VERSION 5.8 ;
NAMESCASESENSITIVE ON ;
BUSBITCHARS "[]" ;
DIVIDERCHAR "/" ;

PROPERTYDEFINITIONS
END PROPERTYDEFINITIONS

UNITS
    DATABASE MICRONS 2000 ;
END UNITS

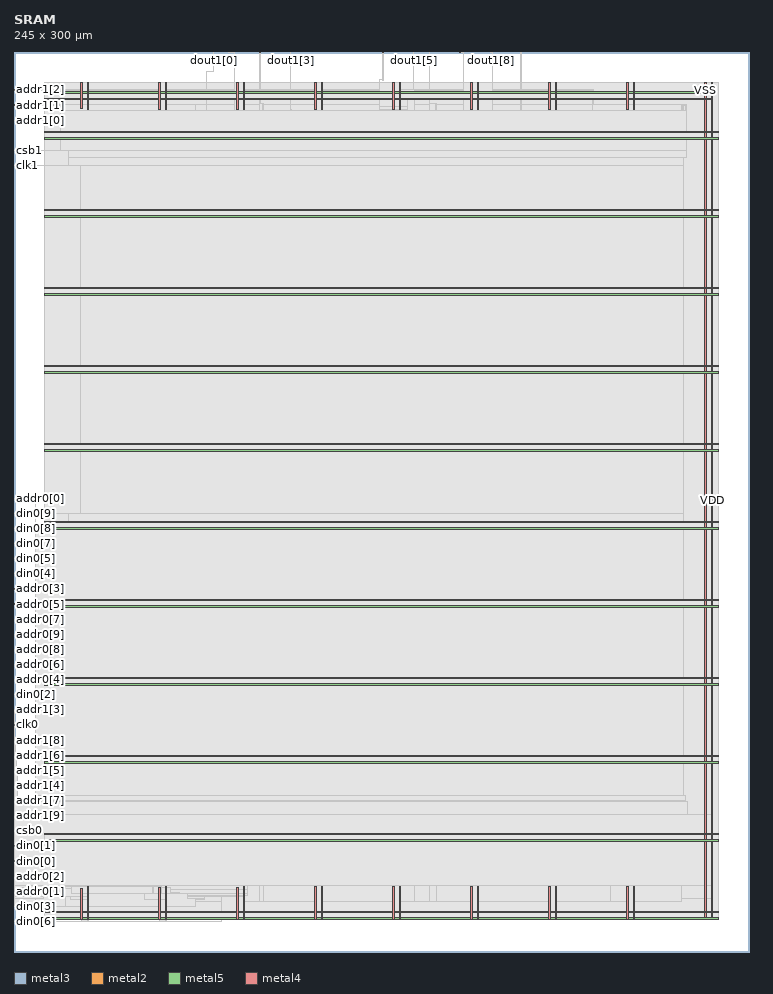
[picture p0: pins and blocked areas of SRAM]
MACRO SRAM
    CLASS BLOCK ;
    SIZE 245 BY 300 ;
    PIN addr0[0]
        DIRECTION INPUT ; 
        USE SIGNAL ; 
        PORT
            LAYER metal3 ;
              RECT  0 151.235 0.07 151.305 ;
        END
    END addr0[0]
    PIN addr0[1]
        DIRECTION INPUT ; 
        USE SIGNAL ; 
        PORT
            LAYER metal3 ;
              RECT  0 20.195 0.07 20.265 ;
        END
    END addr0[1]
    PIN addr0[2]
        DIRECTION INPUT ; 
        USE SIGNAL ; 
        PORT
            LAYER metal3 ;
              RECT  0 25.235 0.07 25.305 ;
        END
    END addr0[2]
    PIN addr0[3]
        DIRECTION INPUT ; 
        USE SIGNAL ; 
        PORT
            LAYER metal3 ;
              RECT  0 120.995 0.07 121.065 ;
        END
    END addr0[3]
    PIN addr0[4]
        DIRECTION INPUT ; 
        USE SIGNAL ; 
        PORT
            LAYER metal3 ;
              RECT  0 90.755 0.07 90.825 ;
        END
    END addr0[4]
    PIN addr0[5]
        DIRECTION INPUT ; 
        USE SIGNAL ; 
        PORT
            LAYER metal3 ;
              RECT  0 115.955 0.07 116.025 ;
        END
    END addr0[5]
    PIN addr0[6]
        DIRECTION INPUT ; 
        USE SIGNAL ; 
        PORT
            LAYER metal3 ;
              RECT  0 95.795 0.07 95.865 ;
        END
    END addr0[6]
    PIN addr0[7]
        DIRECTION INPUT ; 
        USE SIGNAL ; 
        PORT
            LAYER metal3 ;
              RECT  0 110.915 0.07 110.985 ;
        END
    END addr0[7]
    PIN addr0[8]
        DIRECTION INPUT ; 
        USE SIGNAL ; 
        PORT
            LAYER metal3 ;
              RECT  0 100.835 0.07 100.905 ;
        END
    END addr0[8]
    PIN addr0[9]
        DIRECTION INPUT ; 
        USE SIGNAL ; 
        PORT
            LAYER metal3 ;
              RECT  0 105.875 0.07 105.945 ;
        END
    END addr0[9]
    PIN addr1[0]
        DIRECTION INPUT ; 
        USE SIGNAL ; 
        PORT
            LAYER metal3 ;
              RECT  0 277.235 0.07 277.305 ;
        END
    END addr1[0]
    PIN addr1[1]
        DIRECTION INPUT ; 
        USE SIGNAL ; 
        PORT
            LAYER metal3 ;
              RECT  0 282.275 0.07 282.345 ;
        END
    END addr1[1]
    PIN addr1[2]
        DIRECTION INPUT ; 
        USE SIGNAL ; 
        PORT
            LAYER metal3 ;
              RECT  0 287.315 0.07 287.385 ;
        END
    END addr1[2]
    PIN addr1[3]
        DIRECTION INPUT ; 
        USE SIGNAL ; 
        PORT
            LAYER metal3 ;
              RECT  0 80.675 0.07 80.745 ;
        END
    END addr1[3]
    PIN addr1[4]
        DIRECTION INPUT ; 
        USE SIGNAL ; 
        PORT
            LAYER metal3 ;
              RECT  0 55.475 0.07 55.545 ;
        END
    END addr1[4]
    PIN addr1[5]
        DIRECTION INPUT ; 
        USE SIGNAL ; 
        PORT
            LAYER metal3 ;
              RECT  0 60.515 0.07 60.585 ;
        END
    END addr1[5]
    PIN addr1[6]
        DIRECTION INPUT ; 
        USE SIGNAL ; 
        PORT
            LAYER metal3 ;
              RECT  0 65.555 0.07 65.625 ;
        END
    END addr1[6]
    PIN addr1[7]
        DIRECTION INPUT ; 
        USE SIGNAL ; 
        PORT
            LAYER metal3 ;
              RECT  0 50.435 0.07 50.505 ;
        END
    END addr1[7]
    PIN addr1[8]
        DIRECTION INPUT ; 
        USE SIGNAL ; 
        PORT
            LAYER metal3 ;
              RECT  0 70.595 0.07 70.665 ;
        END
    END addr1[8]
    PIN addr1[9]
        DIRECTION INPUT ; 
        USE SIGNAL ; 
        PORT
            LAYER metal3 ;
              RECT  0 45.395 0.07 45.465 ;
        END
    END addr1[9]
    PIN clk0
        DIRECTION INPUT ; 
        USE CLOCK ; 
        PORT
            LAYER metal3 ;
              RECT  0 75.635 0.07 75.705 ;
        END
    END clk0
    PIN clk1
        DIRECTION INPUT ; 
        USE CLOCK ; 
        PORT
            LAYER metal3 ;
              RECT  0 262.115 0.07 262.185 ;
        END
    END clk1
    PIN csb0
        DIRECTION INPUT ; 
        USE SIGNAL ; 
        PORT
            LAYER metal3 ;
              RECT  0 40.355 0.07 40.425 ;
        END
    END csb0
    PIN csb1
        DIRECTION INPUT ; 
        USE SIGNAL ; 
        PORT
            LAYER metal3 ;
              RECT  0 267.155 0.07 267.225 ;
        END
    END csb1
    PIN din0[0]
        DIRECTION INPUT ; 
        USE SIGNAL ; 
        PORT
            LAYER metal3 ;
              RECT  0 30.275 0.07 30.345 ;
        END
    END din0[0]
    PIN din0[1]
        DIRECTION INPUT ; 
        USE SIGNAL ; 
        PORT
            LAYER metal3 ;
              RECT  0 35.315 0.07 35.385 ;
        END
    END din0[1]
    PIN din0[2]
        DIRECTION INPUT ; 
        USE SIGNAL ; 
        PORT
            LAYER metal3 ;
              RECT  0 85.715 0.07 85.785 ;
        END
    END din0[2]
    PIN din0[3]
        DIRECTION INPUT ; 
        USE SIGNAL ; 
        PORT
            LAYER metal3 ;
              RECT  0 15.155 0.07 15.225 ;
        END
    END din0[3]
    PIN din0[4]
        DIRECTION INPUT ; 
        USE SIGNAL ; 
        PORT
            LAYER metal3 ;
              RECT  0 126.035 0.07 126.105 ;
        END
    END din0[4]
    PIN din0[5]
        DIRECTION INPUT ; 
        USE SIGNAL ; 
        PORT
            LAYER metal3 ;
              RECT  0 131.075 0.07 131.145 ;
        END
    END din0[5]
    PIN din0[6]
        DIRECTION INPUT ; 
        USE SIGNAL ; 
        PORT
            LAYER metal3 ;
              RECT  0 10.115 0.07 10.185 ;
        END
    END din0[6]
    PIN din0[7]
        DIRECTION INPUT ; 
        USE SIGNAL ; 
        PORT
            LAYER metal3 ;
              RECT  0 136.115 0.07 136.185 ;
        END
    END din0[7]
    PIN din0[8]
        DIRECTION INPUT ; 
        USE SIGNAL ; 
        PORT
            LAYER metal3 ;
              RECT  0 141.155 0.07 141.225 ;
        END
    END din0[8]
    PIN din0[9]
        DIRECTION INPUT ; 
        USE SIGNAL ; 
        PORT
            LAYER metal3 ;
              RECT  0 146.195 0.07 146.265 ;
        END
    END din0[9]
    PIN dout1[0]
        DIRECTION OUTPUT ; 
        USE SIGNAL ; 
        PORT
            LAYER metal2 ;
              RECT  66.56 299.93 66.63 300 ;
        END
    END dout1[0]
    PIN dout1[1]
        DIRECTION OUTPUT ; 
        USE SIGNAL ; 
        PORT
            LAYER metal2 ;
              RECT  71.69 299.93 71.76 300 ;
        END
    END dout1[1]
    PIN dout1[2]
        DIRECTION OUTPUT ; 
        USE SIGNAL ; 
        PORT
            LAYER metal2 ;
              RECT  81.95 299.93 82.02 300 ;
        END
    END dout1[2]
    PIN dout1[3]
        DIRECTION OUTPUT ; 
        USE SIGNAL ; 
        PORT
            LAYER metal2 ;
              RECT  92.21 299.93 92.28 300 ;
        END
    END dout1[3]
    PIN dout1[4]
        DIRECTION OUTPUT ; 
        USE SIGNAL ; 
        PORT
            LAYER metal2 ;
              RECT  122.99 299.93 123.06 300 ;
        END
    END dout1[4]
    PIN dout1[5]
        DIRECTION OUTPUT ; 
        USE SIGNAL ; 
        PORT
            LAYER metal2 ;
              RECT  133.25 299.93 133.32 300 ;
        END
    END dout1[5]
    PIN dout1[6]
        DIRECTION OUTPUT ; 
        USE SIGNAL ; 
        PORT
            LAYER metal2 ;
              RECT  138.38 299.93 138.45 300 ;
        END
    END dout1[6]
    PIN dout1[7]
        DIRECTION OUTPUT ; 
        USE SIGNAL ; 
        PORT
            LAYER metal2 ;
              RECT  148.64 299.93 148.71 300 ;
        END
    END dout1[7]
    PIN dout1[8]
        DIRECTION OUTPUT ; 
        USE SIGNAL ; 
        PORT
            LAYER metal2 ;
              RECT  158.9 299.93 158.97 300 ;
        END
    END dout1[8]
    PIN dout1[9]
        DIRECTION OUTPUT ; 
        USE SIGNAL ; 
        PORT
            LAYER metal2 ;
              RECT  169.16 299.93 169.23 300 ;
        END
    END dout1[9]
    PIN VSS
        DIRECTION INOUT ; 
        USE GROUND ; 
        PORT
            LAYER metal5 ;
              RECT  10.07 286.26 232.92 286.76 ;
              RECT  10.07 270.95 234.84 271.45 ;
              RECT  10.07 244.95 234.84 245.45 ;
              RECT  10.07 218.95 234.84 219.45 ;
              RECT  10.07 192.95 234.84 193.45 ;
              RECT  10.07 166.95 234.84 167.45 ;
              RECT  10.07 140.95 234.84 141.45 ;
              RECT  10.07 114.95 234.84 115.45 ;
              RECT  10.07 88.95 234.84 89.45 ;
              RECT  10.07 62.95 234.84 63.45 ;
              RECT  10.07 36.95 234.84 37.45 ;
              RECT  10.07 10.95 234.84 11.45 ;
            LAYER metal4 ;
              RECT  230.32 10.95 230.82 289.84 ;
              RECT  204.32 280.82 204.82 289.84 ;
              RECT  204.32 10.95 204.82 21.79 ;
              RECT  178.32 280.82 178.82 289.84 ;
              RECT  178.32 10.95 178.82 21.79 ;
              RECT  152.32 280.82 152.82 289.84 ;
              RECT  152.32 10.95 152.82 21.79 ;
              RECT  126.32 280.82 126.82 289.84 ;
              RECT  126.32 10.95 126.82 21.79 ;
              RECT  100.32 280.82 100.82 289.84 ;
              RECT  100.32 10.95 100.82 21.79 ;
              RECT  74.32 280.82 74.82 289.84 ;
              RECT  74.32 10.95 74.82 21.65 ;
              RECT  48.32 280.82 48.82 289.84 ;
              RECT  48.32 10.95 48.82 21.65 ;
              RECT  22.32 281.32 22.82 289.84 ;
              RECT  22.32 10.95 22.82 21.29 ;
        END
    END VSS
    PIN VDD
        DIRECTION INOUT ; 
        USE POWER ; 
        PORT
            LAYER metal5 ;
              RECT  10.07 284.02 232.92 284.52 ;
              RECT  10.07 273.05 234.84 273.55 ;
              RECT  10.07 247.05 234.84 247.55 ;
              RECT  10.07 221.05 234.84 221.55 ;
              RECT  10.07 195.05 234.84 195.55 ;
              RECT  10.07 169.05 234.84 169.55 ;
              RECT  10.07 143.05 234.84 143.55 ;
              RECT  10.07 117.05 234.84 117.55 ;
              RECT  10.07 91.05 234.84 91.55 ;
              RECT  10.07 65.05 234.84 65.55 ;
              RECT  10.07 39.05 234.84 39.55 ;
              RECT  10.07 13.05 234.84 13.55 ;
            LAYER metal4 ;
              RECT  232.42 11.16 232.92 289.87 ;
              RECT  206.42 280.82 206.92 289.87 ;
              RECT  206.42 11.16 206.92 21.79 ;
              RECT  180.42 280.82 180.92 289.87 ;
              RECT  180.42 11.16 180.92 21.79 ;
              RECT  154.42 280.82 154.92 289.87 ;
              RECT  154.42 11.16 154.92 21.79 ;
              RECT  128.42 280.82 128.92 289.87 ;
              RECT  128.42 11.16 128.92 21.79 ;
              RECT  102.42 280.82 102.92 289.87 ;
              RECT  102.42 11.16 102.92 21.79 ;
              RECT  76.42 280.82 76.92 289.87 ;
              RECT  76.42 11.16 76.92 21.79 ;
              RECT  50.42 280.82 50.92 289.87 ;
              RECT  50.42 11.16 50.92 21.79 ;
              RECT  24.42 280.82 24.92 289.87 ;
              RECT  24.42 11.16 24.92 21.79 ;
        END
    END VDD
    OBS
      LAYER metal1 ;
        RECT  10.07 11.115 234.84 289.885 ;
      LAYER metal2 ;
        RECT  22.34 11.13 22.8 12.53 ;
        RECT  48.34 11.13 48.8 12.53 ;
        RECT  74.34 11.13 74.8 12.53 ;
        RECT  100.34 11.13 100.8 12.53 ;
        RECT  126.34 11.13 126.8 12.53 ;
        RECT  152.34 11.13 152.8 12.53 ;
        RECT  178.34 11.13 178.8 12.53 ;
        RECT  204.34 11.13 204.8 12.53 ;
        RECT  230.34 11.13 230.8 12.53 ;
        RECT  223.31 18.34 223.38 19.88 ;
        RECT  22.34 12.53 24.9 22.2 ;
        RECT  48.34 12.53 50.9 22.2 ;
        RECT  74.34 12.53 76.9 22.2 ;
        RECT  100.34 12.53 102.9 22.2 ;
        RECT  126.34 12.53 128.9 22.2 ;
        RECT  152.34 12.53 154.9 22.2 ;
        RECT  178.34 12.53 180.9 22.2 ;
        RECT  204.34 12.53 206.9 22.2 ;
        RECT  223.12 19.88 223.38 22.2 ;
        RECT  22.295 22.2 223.38 43.05 ;
        RECT  22.295 43.05 223.19 55.02 ;
        RECT  22.295 55.02 222.96 280.41 ;
        RECT  22.34 280.41 24.9 288.47 ;
        RECT  48.34 280.41 50.9 288.47 ;
        RECT  74.34 280.41 76.9 288.47 ;
        RECT  100.34 280.41 102.9 288.47 ;
        RECT  126.34 280.41 128.9 288.47 ;
        RECT  152.34 280.41 154.9 288.47 ;
        RECT  178.34 280.41 180.9 288.47 ;
        RECT  204.34 280.41 206.9 288.47 ;
        RECT  230.34 12.53 232.9 288.47 ;
        RECT  24.44 288.47 24.9 289.87 ;
        RECT  50.44 288.47 50.9 289.87 ;
        RECT  76.44 288.47 76.9 289.87 ;
        RECT  102.44 288.47 102.9 289.87 ;
        RECT  128.44 288.47 128.9 289.87 ;
        RECT  154.44 288.47 154.9 289.87 ;
        RECT  180.44 288.47 180.9 289.87 ;
        RECT  206.44 288.47 206.9 289.87 ;
        RECT  232.44 288.47 232.9 289.87 ;
        RECT  66.56 293.44 66.63 299.965 ;
        RECT  71.69 299.74 71.76 299.965 ;
        RECT  81.95 280.41 82.02 299.965 ;
        RECT  92.21 299.74 92.28 299.965 ;
        RECT  122.99 290.64 123.06 299.965 ;
        RECT  133.25 284.9 133.32 299.965 ;
        RECT  138.38 280.41 138.45 299.965 ;
        RECT  148.64 299.74 148.71 299.965 ;
        RECT  158.9 299.74 158.97 299.965 ;
        RECT  169.16 299.74 169.23 299.965 ;
      LAYER metal3 ;
        RECT  0.025 16.975 0.035 17.045 ;
        RECT  0.025 80.675 0.165 80.745 ;
        RECT  0.035 15.155 0.305 17.045 ;
        RECT  0.035 20.195 0.305 20.265 ;
        RECT  0.035 70.595 0.445 70.665 ;
        RECT  0.035 65.555 0.725 65.625 ;
        RECT  0.035 60.515 1.005 60.585 ;
        RECT  0.035 55.475 1.285 55.545 ;
        RECT  0.035 50.435 1.565 50.505 ;
        RECT  0.035 45.395 1.845 45.465 ;
        RECT  0.035 30.275 2.125 30.345 ;
        RECT  0.035 151.235 7.165 151.305 ;
        RECT  0.035 85.715 9.965 85.785 ;
        RECT  0.035 35.315 11.505 35.385 ;
        RECT  0.035 25.235 11.645 25.305 ;
        RECT  0.035 40.355 11.645 40.425 ;
        RECT  0.035 141.155 12.765 141.225 ;
        RECT  0.035 282.275 15.425 282.345 ;
        RECT  0.035 131.075 15.565 131.145 ;
        RECT  0.035 267.155 15.565 267.225 ;
        RECT  0.035 120.995 15.845 121.065 ;
        RECT  15.425 282.275 17.105 282.485 ;
        RECT  0.305 15.155 17.245 20.265 ;
        RECT  0.035 277.235 17.245 277.305 ;
        RECT  17.105 282.275 18.225 282.625 ;
        RECT  0.035 146.195 18.365 146.265 ;
        RECT  0.035 262.115 18.365 262.185 ;
        RECT  0.035 136.115 18.645 136.185 ;
        RECT  0.035 126.035 18.925 126.105 ;
        RECT  0.035 90.755 19.065 90.825 ;
        RECT  11.505 35.315 19.205 37.205 ;
        RECT  0.035 115.955 19.205 116.025 ;
        RECT  0.035 95.795 19.905 95.865 ;
        RECT  0.035 100.835 20.185 100.905 ;
        RECT  19.205 37.135 21.305 37.205 ;
        RECT  19.065 90.755 21.62 92.785 ;
        RECT  19.905 95.795 21.62 97.685 ;
        RECT  17.245 15.155 22.155 19.845 ;
        RECT  21.305 37.135 22.155 38.325 ;
        RECT  15.705 87.675 22.155 87.745 ;
        RECT  21.62 90.755 22.155 97.685 ;
        RECT  20.185 100.835 22.155 102.585 ;
        RECT  18.225 282.135 22.155 282.625 ;
        RECT  22.155 15.155 22.295 22.76 ;
        RECT  22.155 37.1 22.295 38.325 ;
        RECT  0.035 75.635 22.295 75.705 ;
        RECT  22.155 87.67 22.295 102.63 ;
        RECT  0.035 105.875 22.295 105.945 ;
        RECT  0.035 110.915 22.295 110.985 ;
        RECT  22.155 279.85 22.295 282.625 ;
        RECT  0.035 10.115 22.34 10.185 ;
        RECT  22.295 15.155 22.34 282.625 ;
        RECT  0.035 287.315 22.34 287.385 ;
        RECT  22.34 10.115 24.44 288.47 ;
        RECT  24.44 10.115 24.9 289.87 ;
        RECT  24.9 10.115 48.34 10.185 ;
        RECT  24.9 15.155 48.34 282.625 ;
        RECT  24.9 287.315 48.34 287.385 ;
        RECT  48.34 10.115 50.44 288.47 ;
        RECT  50.44 10.115 50.9 289.87 ;
        RECT  50.9 15.155 60.645 282.625 ;
        RECT  64.145 293.475 66.665 293.545 ;
        RECT  50.9 10.115 69.325 10.185 ;
        RECT  71.655 299.775 73.525 299.845 ;
        RECT  60.645 16.975 74.34 282.625 ;
        RECT  50.9 287.315 74.34 287.385 ;
        RECT  74.34 11.13 74.8 288.47 ;
        RECT  74.8 12.53 76.44 288.47 ;
        RECT  76.44 12.53 76.9 289.87 ;
        RECT  76.9 16.975 81.915 282.625 ;
        RECT  81.915 16.975 83.045 282.765 ;
        RECT  92.145 299.775 92.315 299.845 ;
        RECT  83.045 16.975 100.34 282.625 ;
        RECT  76.9 287.315 100.34 287.385 ;
        RECT  100.34 11.13 100.8 288.47 ;
        RECT  100.8 12.53 102.44 288.47 ;
        RECT  102.44 12.53 102.9 289.87 ;
        RECT  121.825 290.675 123.095 290.745 ;
        RECT  102.9 16.975 126.34 282.625 ;
        RECT  102.9 287.315 126.34 287.385 ;
        RECT  126.34 11.13 126.8 288.47 ;
        RECT  126.8 12.53 128.44 288.47 ;
        RECT  128.44 12.53 128.9 289.87 ;
        RECT  128.9 16.975 133.355 287.385 ;
        RECT  133.355 16.975 138.345 282.625 ;
        RECT  138.345 16.975 140.725 282.765 ;
        RECT  148.605 299.775 149.965 299.845 ;
        RECT  140.725 16.975 152.34 282.625 ;
        RECT  133.355 287.315 152.34 287.385 ;
        RECT  152.34 11.13 152.8 288.47 ;
        RECT  152.8 12.53 154.44 288.47 ;
        RECT  154.44 12.53 154.9 289.87 ;
        RECT  158.865 299.775 159.485 299.845 ;
        RECT  168.865 299.775 169.265 299.845 ;
        RECT  154.9 16.975 178.34 282.625 ;
        RECT  154.9 287.315 178.34 287.385 ;
        RECT  178.34 11.13 178.8 288.47 ;
        RECT  178.8 12.53 180.44 288.47 ;
        RECT  180.44 12.53 180.9 289.87 ;
        RECT  180.9 287.315 193.085 287.385 ;
        RECT  180.9 16.975 198.965 282.625 ;
        RECT  198.965 16.975 204.34 282.485 ;
        RECT  204.34 11.13 204.8 288.47 ;
        RECT  204.8 12.53 206.44 288.47 ;
        RECT  206.44 12.53 206.9 289.87 ;
        RECT  206.9 16.975 222.485 282.485 ;
        RECT  222.485 17.815 222.96 282.485 ;
        RECT  222.96 17.815 223.1 22.76 ;
        RECT  222.96 40.74 223.1 55.7 ;
        RECT  222.96 264.705 223.1 265.08 ;
        RECT  222.96 279.85 223.1 282.485 ;
        RECT  223.1 17.815 223.225 19.985 ;
        RECT  223.1 54.915 223.225 54.985 ;
        RECT  223.1 40.775 223.415 52.045 ;
        RECT  223.1 264.775 223.57 265.01 ;
        RECT  223.415 45.675 223.885 52.045 ;
        RECT  223.57 264.775 223.885 264.985 ;
        RECT  223.1 282.135 223.885 282.485 ;
        RECT  223.225 17.815 224.165 19.845 ;
        RECT  223.885 45.675 224.165 50.085 ;
        RECT  223.885 264.915 224.165 264.985 ;
        RECT  223.885 282.415 224.165 282.485 ;
        RECT  224.165 17.815 224.445 19.285 ;
        RECT  224.165 50.015 224.445 50.085 ;
        RECT  224.445 17.815 224.725 19.145 ;
        RECT  224.165 45.675 224.725 45.745 ;
        RECT  224.725 17.815 225.005 17.885 ;
        RECT  223.415 40.775 225.005 40.845 ;
        RECT  230.34 11.13 230.8 288.47 ;
        RECT  230.8 12.53 232.44 288.47 ;
        RECT  232.44 12.53 232.9 289.87 ;
      LAYER metal4 ;
        RECT  69.185 10.08 69.325 10.95 ;
        RECT  22.32 10.95 22.82 11.16 ;
        RECT  48.32 10.95 48.82 11.16 ;
        RECT  69.185 10.95 74.82 11.16 ;
        RECT  100.32 10.95 100.82 11.16 ;
        RECT  126.32 10.95 126.82 11.16 ;
        RECT  152.32 10.95 152.82 11.16 ;
        RECT  178.32 10.95 178.82 11.16 ;
        RECT  204.32 10.95 204.82 11.16 ;
        RECT  230.32 10.95 230.82 11.16 ;
        RECT  48.32 11.16 50.92 17.5 ;
        RECT  22.32 11.16 24.92 17.64 ;
        RECT  60.505 15.12 60.645 17.64 ;
        RECT  0.025 16.94 0.165 17.78 ;
        RECT  7.025 17.5 7.165 17.78 ;
        RECT  222.345 16.94 222.485 17.78 ;
        RECT  230.32 11.16 232.92 17.78 ;
        RECT  0.025 17.78 7.165 17.92 ;
        RECT  60.505 17.64 63.445 17.92 ;
        RECT  0.025 17.92 9.965 18.48 ;
        RECT  18.785 17.64 24.92 18.48 ;
        RECT  57.705 17.92 63.445 18.48 ;
        RECT  69.185 11.16 76.92 18.48 ;
        RECT  57.705 18.48 76.92 18.76 ;
        RECT  43.425 17.5 50.92 19.6 ;
        RECT  57.705 18.76 77.725 19.6 ;
        RECT  43.425 19.6 77.725 20.72 ;
        RECT  0.025 18.48 24.92 22.2 ;
        RECT  43.425 20.72 77.885 22.2 ;
        RECT  100.32 11.16 102.92 22.2 ;
        RECT  126.32 11.16 128.92 22.2 ;
        RECT  152.32 11.16 154.92 22.2 ;
        RECT  178.32 11.16 180.92 22.2 ;
        RECT  204.32 11.16 206.92 22.2 ;
        RECT  222.345 17.78 232.92 22.2 ;
        RECT  0.025 22.2 232.92 45.78 ;
        RECT  0.025 45.78 224.445 50.12 ;
        RECT  0.025 50.12 223.885 50.54 ;
        RECT  7.025 50.54 223.885 52.08 ;
        RECT  0.025 50.54 1.285 55.58 ;
        RECT  0.025 55.58 1.005 60.62 ;
        RECT  0.025 60.62 0.725 65.66 ;
        RECT  0.025 65.66 0.445 70.7 ;
        RECT  0.025 70.7 0.165 80.78 ;
        RECT  7.025 52.08 223.1 141.26 ;
        RECT  18.225 141.26 223.1 146.3 ;
        RECT  7.025 141.26 7.165 151.34 ;
        RECT  22.155 146.3 223.1 262.08 ;
        RECT  18.225 262.08 223.1 264.74 ;
        RECT  18.225 264.74 223.885 264.88 ;
        RECT  18.225 264.88 224.165 267.12 ;
        RECT  15.425 267.12 224.165 280.41 ;
        RECT  222.4 280.41 224.165 280.55 ;
        RECT  82.885 280.41 83.045 280.98 ;
        RECT  92.145 280.41 92.425 280.98 ;
        RECT  121.745 280.41 131.285 280.98 ;
        RECT  140.545 280.41 140.725 280.98 ;
        RECT  168.745 280.41 169.005 280.98 ;
        RECT  64.085 280.41 64.285 281.82 ;
        RECT  121.825 280.98 131.285 281.82 ;
        RECT  223.745 280.55 224.165 282.24 ;
        RECT  192.945 280.41 206.92 282.38 ;
        RECT  15.425 280.41 24.92 282.52 ;
        RECT  224.025 282.24 224.165 282.52 ;
        RECT  17.105 282.52 24.92 282.66 ;
        RECT  198.825 282.38 206.92 282.66 ;
        RECT  82.905 280.98 83.045 282.8 ;
        RECT  140.585 280.98 140.725 282.8 ;
        RECT  121.825 281.82 131.205 285.04 ;
        RECT  192.945 282.38 193.085 287.42 ;
        RECT  22.32 282.66 24.92 289.84 ;
        RECT  48.32 280.41 50.92 289.84 ;
        RECT  100.32 280.41 102.92 289.84 ;
        RECT  121.825 285.04 128.92 289.84 ;
        RECT  178.32 280.41 180.92 289.84 ;
        RECT  204.32 282.66 206.92 289.84 ;
        RECT  230.32 45.78 232.92 289.84 ;
        RECT  24.42 289.84 24.92 289.87 ;
        RECT  50.42 289.84 50.92 289.87 ;
        RECT  73.385 280.41 76.92 289.87 ;
        RECT  102.42 289.84 102.92 289.87 ;
        RECT  128.42 289.84 128.92 289.87 ;
        RECT  149.825 280.41 159.485 289.87 ;
        RECT  180.42 289.84 180.92 289.87 ;
        RECT  206.42 289.84 206.92 289.87 ;
        RECT  232.42 289.84 232.92 289.87 ;
        RECT  121.825 289.84 121.965 290.78 ;
        RECT  64.145 281.82 64.285 293.58 ;
        RECT  73.385 289.87 73.525 299.88 ;
        RECT  92.145 280.98 92.285 299.88 ;
        RECT  149.825 289.87 149.965 299.88 ;
        RECT  159.345 289.87 159.485 299.88 ;
        RECT  168.865 280.98 169.005 299.88 ;
      LAYER metal5 ;
        RECT  1.985 21.28 11.505 21.42 ;
        RECT  11.505 21.28 17.105 21.7 ;
        RECT  17.105 21.28 19.065 21.98 ;
        RECT  19.065 19.6 46.225 21.98 ;
        RECT  46.225 19.6 46.365 22.2 ;
        RECT  46.365 19.6 49.285 21.7 ;
        RECT  49.285 19.6 52.145 21.42 ;
        RECT  52.145 19.6 55.045 19.74 ;
        RECT  10.07 284.02 232.92 286.76 ;
        RECT  10.07 10.95 234.84 13.55 ;
        RECT  10.07 36.95 234.84 39.55 ;
        RECT  10.07 62.95 234.84 65.55 ;
        RECT  10.07 88.95 234.84 91.55 ;
        RECT  10.07 114.95 234.84 117.55 ;
        RECT  10.07 140.95 234.84 143.55 ;
        RECT  10.07 166.95 234.84 169.55 ;
        RECT  10.07 192.95 234.84 195.55 ;
        RECT  10.07 218.95 234.84 221.55 ;
        RECT  10.07 244.95 234.84 247.55 ;
        RECT  10.07 270.95 234.84 273.55 ;
    END
END SRAM
END LIBRARY
